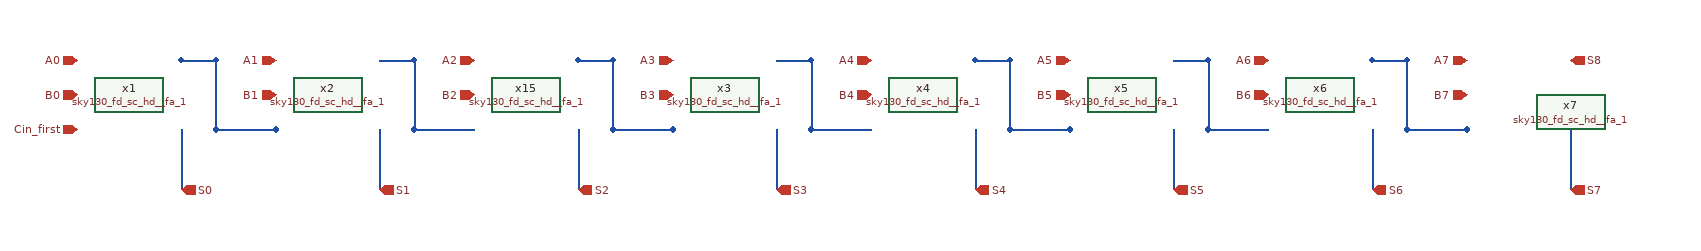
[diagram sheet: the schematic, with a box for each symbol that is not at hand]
v {xschem version=3.1.0 file_version=1.2
}
G {}
K {}
V {}
S {}
E {}
N 270 -330 310 -330 {
lab=#net1}
N 310 -330 310 -250 {
lab=#net1}
N 310 -250 380 -250 {
lab=#net1}
N 500 -250 500 -180 {
lab=S1}
N 270 -330 310 -330 {
lab=#net1}
N 310 -330 310 -250 {
lab=#net1}
N 310 -250 380 -250 {
lab=#net1}
N 270 -250 270 -180 {
lab=S0}
N 270 -330 310 -330 {
lab=#net1}
N 310 -330 310 -250 {
lab=#net1}
N 310 -250 380 -250 {
lab=#net1}
N 500 -250 500 -180 {
lab=S1}
N 270 -250 270 -180 {
lab=S0}
N 270 -330 310 -330 {
lab=#net1}
N 310 -330 310 -250 {
lab=#net1}
N 310 -250 380 -250 {
lab=#net1}
N 730 -330 770 -330 {
lab=#net2}
N 770 -330 770 -250 {
lab=#net2}
N 770 -250 840 -250 {
lab=#net2}
N 960 -250 960 -180 {
lab=S3}
N 730 -330 770 -330 {
lab=#net2}
N 770 -330 770 -250 {
lab=#net2}
N 770 -250 840 -250 {
lab=#net2}
N 730 -250 730 -180 {
lab=S2}
N 730 -330 770 -330 {
lab=#net2}
N 770 -330 770 -250 {
lab=#net2}
N 770 -250 840 -250 {
lab=#net2}
N 960 -250 960 -180 {
lab=S3}
N 730 -250 730 -180 {
lab=S2}
N 730 -330 770 -330 {
lab=#net2}
N 770 -330 770 -250 {
lab=#net2}
N 770 -250 840 -250 {
lab=#net2}
N 500 -330 540 -330 {
lab=#net3}
N 540 -250 610 -250 {
lab=#net3}
N 500 -330 540 -330 {
lab=#net3}
N 540 -250 610 -250 {
lab=#net3}
N 540 -330 540 -250 {
lab=#net3}
N 1190 -330 1230 -330 {
lab=#net4}
N 1230 -330 1230 -250 {
lab=#net4}
N 1230 -250 1300 -250 {
lab=#net4}
N 1420 -250 1420 -180 {
lab=S5}
N 1190 -330 1230 -330 {
lab=#net4}
N 1230 -330 1230 -250 {
lab=#net4}
N 1230 -250 1300 -250 {
lab=#net4}
N 1190 -250 1190 -180 {
lab=S4}
N 1190 -330 1230 -330 {
lab=#net4}
N 1230 -330 1230 -250 {
lab=#net4}
N 1230 -250 1300 -250 {
lab=#net4}
N 1420 -250 1420 -180 {
lab=S5}
N 1190 -250 1190 -180 {
lab=S4}
N 1190 -330 1230 -330 {
lab=#net4}
N 1230 -330 1230 -250 {
lab=#net4}
N 1230 -250 1300 -250 {
lab=#net4}
N 960 -330 1000 -330 {
lab=#net5}
N 1000 -250 1070 -250 {
lab=#net5}
N 960 -330 1000 -330 {
lab=#net5}
N 1000 -250 1070 -250 {
lab=#net5}
N 1000 -330 1000 -250 {
lab=#net5}
N 1650 -330 1690 -330 {
lab=#net6}
N 1690 -330 1690 -250 {
lab=#net6}
N 1690 -250 1760 -250 {
lab=#net6}
N 1650 -330 1690 -330 {
lab=#net6}
N 1690 -330 1690 -250 {
lab=#net6}
N 1690 -250 1760 -250 {
lab=#net6}
N 1650 -250 1650 -180 {
lab=#net7}
N 1650 -330 1690 -330 {
lab=#net6}
N 1690 -330 1690 -250 {
lab=#net6}
N 1690 -250 1760 -250 {
lab=#net6}
N 1650 -250 1650 -180 {
lab=#net7}
N 1650 -330 1690 -330 {
lab=#net6}
N 1690 -330 1690 -250 {
lab=#net6}
N 1690 -250 1760 -250 {
lab=#net6}
N 1420 -330 1460 -330 {
lab=#net8}
N 1460 -250 1530 -250 {
lab=#net8}
N 1420 -330 1460 -330 {
lab=#net8}
N 1460 -250 1530 -250 {
lab=#net8}
N 1460 -330 1460 -250 {
lab=#net8}
N 1880 -250 1880 -180 {
lab=S7}
C {devices/ipin.sym} 150 -330 0 0 {name=p1 lab=A0}
C {devices/ipin.sym} 380 -330 0 0 {name=p2 lab=A1}
C {devices/ipin.sym} 610 -330 0 0 {name=p3 lab=A2}
C {devices/ipin.sym} 840 -330 0 0 {name=p4 lab=A3}
C {devices/ipin.sym} 1070 -330 0 0 {name=p5 lab=A4}
C {devices/ipin.sym} 1300 -330 0 0 {name=p6 lab=A5}
C {devices/ipin.sym} 1530 -330 0 0 {name=p7 lab=A6}
C {devices/ipin.sym} 1760 -330 0 0 {name=p8 lab=A7}
C {devices/ipin.sym} 150 -290 0 0 {name=p9 lab=B0}
C {devices/ipin.sym} 380 -290 0 0 {name=p10 lab=B1}
C {devices/ipin.sym} 610 -290 0 0 {name=p11 lab=B2}
C {devices/ipin.sym} 840 -290 0 0 {name=p12 lab=B3}
C {devices/ipin.sym} 1070 -290 0 0 {name=p13 lab=B4}
C {devices/ipin.sym} 1300 -290 0 0 {name=p14 lab=B5}
C {devices/ipin.sym} 1530 -290 0 0 {name=p15 lab=B6}
C {devices/ipin.sym} 1760 -290 0 0 {name=p16 lab=B7}
C {devices/opin.sym} 270 -180 0 0 {name=p17 lab=S0}
C {devices/opin.sym} 500 -180 0 0 {name=p18 lab=S1}
C {devices/opin.sym} 730 -180 0 0 {name=p19 lab=S2}
C {devices/opin.sym} 960 -180 0 0 {name=p20 lab=S3}
C {devices/opin.sym} 1190 -180 0 0 {name=p21 lab=S4}
C {devices/opin.sym} 1420 -180 0 0 {name=p22 lab=S5}
C {devices/ipin.sym} 150 -250 0 0 {name=p26 lab=Cin_first}
C {sky130_stdcells/sky130_fd_sc_hd__fa_1.sym} 210 -290 0 0 {name=x1 VGND=VGND VNB=VNB VPB=VPB VPWR=VPWR prefix=sky130_fd_sc_hd__ }
C {sky130_stdcells/sky130_fd_sc_hd__fa_1.sym} 440 -290 0 0 {name=x2 VGND=VGND VNB=VNB VPB=VPB VPWR=VPWR prefix=sky130_fd_sc_hd__ }
C {sky130_stdcells/sky130_fd_sc_hd__fa_1.sym} 670 -290 0 0 {name=x15 VGND=VGND VNB=VNB VPB=VPB VPWR=VPWR prefix=sky130_fd_sc_hd__ }
C {sky130_stdcells/sky130_fd_sc_hd__fa_1.sym} 900 -290 0 0 {name=x3 VGND=VGND VNB=VNB VPB=VPB VPWR=VPWR prefix=sky130_fd_sc_hd__ }
C {sky130_stdcells/sky130_fd_sc_hd__fa_1.sym} 1130 -290 0 0 {name=x4 VGND=VGND VNB=VNB VPB=VPB VPWR=VPWR prefix=sky130_fd_sc_hd__ }
C {sky130_stdcells/sky130_fd_sc_hd__fa_1.sym} 1360 -290 0 0 {name=x5 VGND=VGND VNB=VNB VPB=VPB VPWR=VPWR prefix=sky130_fd_sc_hd__ }
C {sky130_stdcells/sky130_fd_sc_hd__fa_1.sym} 1590 -290 0 0 {name=x6 VGND=VGND VNB=VNB VPB=VPB VPWR=VPWR prefix=sky130_fd_sc_hd__ }
C {sky130_stdcells/sky130_fd_sc_hd__fa_1.sym} 1820 -290 0 0 {name=x7 VGND=VGND VNB=VNB VPB=VPB VPWR=VPWR prefix=sky130_fd_sc_hd__ }
C {devices/opin.sym} 1650 -180 0 0 {name=p23 lab=S6}
C {devices/opin.sym} 1880 -180 0 0 {name=p24 lab=S7}
C {devices/opin.sym} 1880 -330 0 0 {name=p25 lab=S8}
